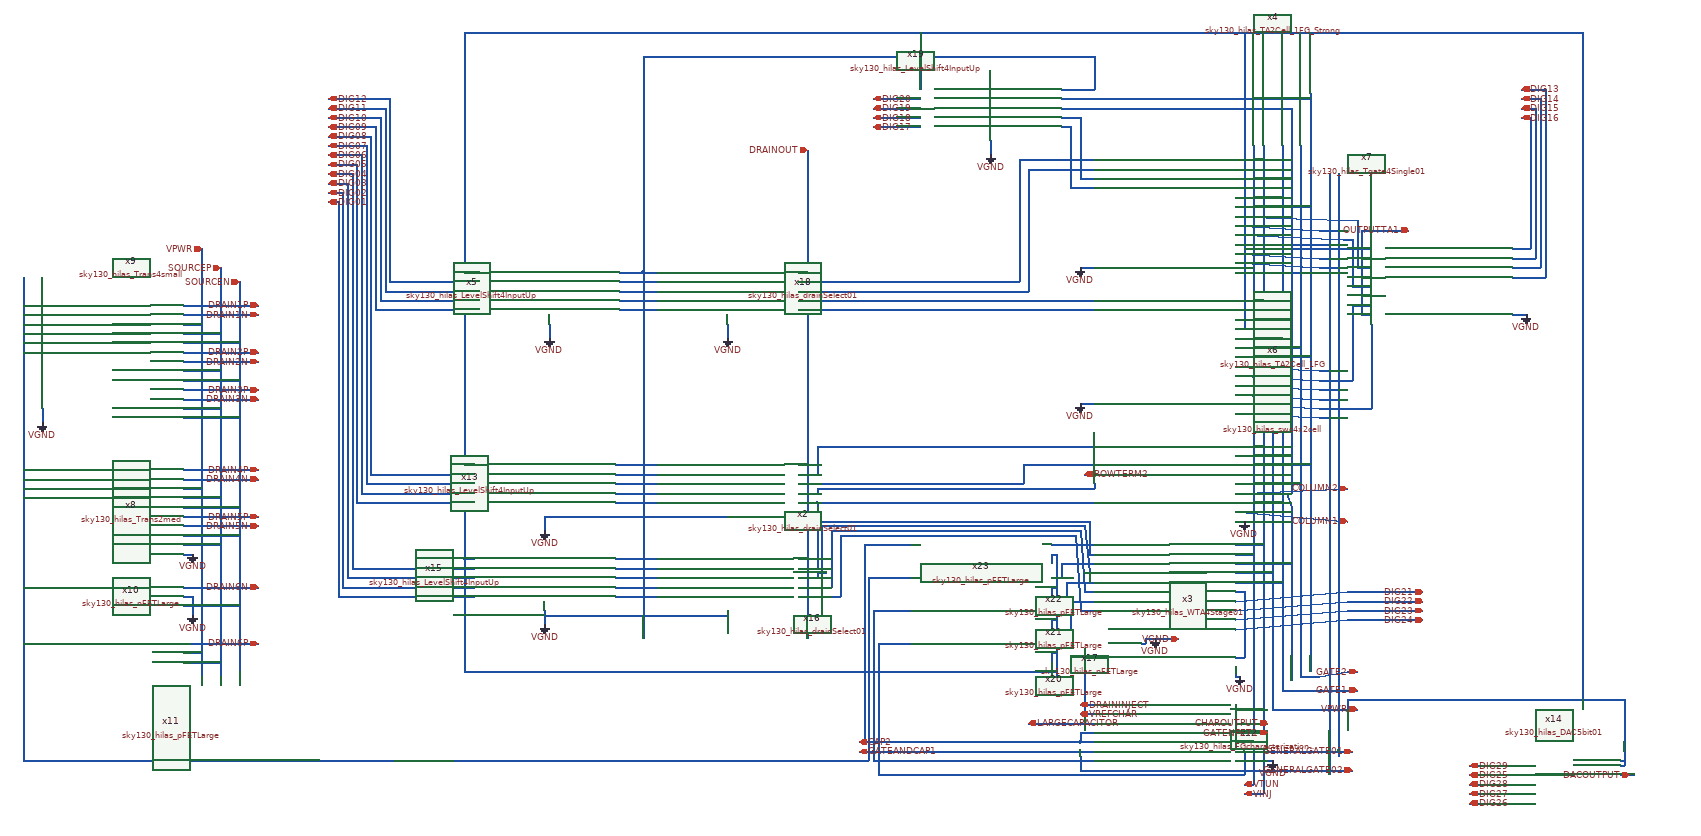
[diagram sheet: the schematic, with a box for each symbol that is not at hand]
v {xschem version=2.9.9 file_version=1.2 }
G {}
K {}
V {}
S {}
E {}
N 800 -10 800 440 { lab=VTUN}
N -500 -10 -500 430 { lab=#net1}
N 820 -10 820 440 { lab=VINJ}
N -500 60 -470 60 { lab=#net1}
N -500 260 -470 260 { lab=#net1}
N 760 20 820 20 { lab=VINJ}
N 760 230 820 230 { lab=VINJ}
N 760 80 800 80 { lab=VTUN}
N 760 250 800 250 { lab=VTUN}
N 840 -10 840 440 { lab=VPWR}
N 760 290 840 290 { lab=VPWR}
N 760 330 780 330 { lab=#net2}
N 780 330 780 460 { lab=#net2}
N -150 -10 -150 430 { lab=DRAINOUT}
N -170 60 -150 60 { lab=DRAINOUT}
N -170 260 -150 260 { lab=DRAINOUT}
N 300 20 460 20 { lab=#net3}
N -130 30 -130 80 { lab=#net3}
N -170 80 -130 80 { lab=#net3}
N 300 140 460 140 { lab=#net4}
N -130 140 -130 150 { lab=#net4}
N -170 140 -130 140 { lab=#net4}
N 300 110 460 110 { lab=#net5}
N -130 110 -130 120 { lab=#net5}
N -170 120 -130 120 { lab=#net5}
N 310 60 460 60 { lab=#net6}
N 310 70 310 100 { lab=#net6}
N -170 100 -120 100 { lab=#net6}
N -170 280 -130 280 { lab=#net7}
N -130 250 -130 280 { lab=#net7}
N -170 340 -130 340 { lab=#net8}
N -170 320 -130 320 { lab=#net9}
N -130 290 -110 290 { lab=#net10}
N -130 290 -130 300 { lab=#net10}
N -170 300 -130 300 { lab=#net10}
N 860 -10 860 500 { lab=GATE1}
N 900 -10 900 500 { lab=GATE2}
N 760 310 860 310 { lab=GATE1}
N 760 140 860 140 { lab=GATE1}
N 920 -10 920 500 { lab=#net11}
N 880 -10 880 120 { lab=#net12}
N 880 150 880 500 { lab=#net12}
N 760 40 880 40 { lab=#net12}
N 760 270 880 270 { lab=#net12}
N 760 60 920 60 { lab=#net11}
N 870 120 880 150 { lab=#net12}
N 870 120 880 120 { lab=#net12}
N 820 440 820 550 { lab=VINJ}
N 820 550 820 720 { lab=VINJ}
N 800 440 800 660 { lab=VTUN}
N 760 650 800 650 { lab=VTUN}
N 760 580 820 580 { lab=VINJ}
N 820 720 820 740 { lab=VINJ}
N 800 660 800 720 { lab=VTUN}
N 820 740 820 760 { lab=VINJ}
N 780 760 820 760 { lab=VINJ}
N 770 630 790 630 { lab=GATENFET1}
N 430 690 460 690 { lab=GENERALGATE02}
N 430 670 460 670 { lab=GATEANDCAP1}
N 430 650 460 650 { lab=CAP2}
N 430 610 460 610 { lab=LARGECAPACITOR}
N 430 590 460 590 { lab=VREFCHAR}
N 430 570 460 570 { lab=DRAININJECT}
N 800 -520 800 -70 { lab=VTUN}
N 820 -520 820 -70 { lab=VINJ}
N 860 -520 860 -10 { lab=GATE1}
N 900 -520 900 -10 { lab=GATE2}
N 920 -520 920 -10 { lab=#net11}
N 880 -520 880 -10 { lab=#net12}
N 800 -70 800 -10 { lab=VTUN}
N 820 -70 820 -10 { lab=VINJ}
N -150 -450 -150 -10 { lab=DRAINOUT}
N -150 -610 -150 -450 { lab=DRAINOUT}
N -170 -350 -150 -350 { lab=DRAINOUT}
N 300 -270 460 -270 { lab=#net13}
N 300 -290 460 -290 { lab=#net14}
N -170 -290 -130 -290 { lab=#net14}
N -170 -270 -130 -270 { lab=#net13}
N -500 -350 -500 -10 { lab=#net1}
N -500 -350 -470 -350 { lab=#net1}
N 430 -610 430 -550 { lab=#net15}
N 410 -610 410 -530 { lab=#net16}
N 430 -550 460 -550 { lab=#net15}
N 410 -530 460 -530 { lab=#net16}
N -170 -330 -130 -330 { lab=#net17}
N 300 -590 300 -330 { lab=#net17}
N 300 -590 460 -590 { lab=#net17}
N -170 -310 -110 -310 { lab=#net18}
N 320 -570 320 -310 { lab=#net18}
N 320 -570 460 -570 { lab=#net18}
N 800 -620 800 -520 { lab=VTUN}
N 820 -620 820 -520 { lab=VINJ}
N 860 -620 860 -520 { lab=GATE1}
N 880 -620 880 -520 { lab=#net12}
N 900 -620 900 -520 { lab=GATE2}
N 920 -620 920 -520 { lab=#net11}
N 760 -590 820 -590 { lab=VINJ}
N 760 -570 800 -570 { lab=VTUN}
N 760 -290 820 -290 { lab=VINJ}
N 760 -270 800 -270 { lab=VTUN}
N 760 -250 880 -250 { lab=#net12}
N 760 -550 880 -550 { lab=#net12}
N 760 -490 920 -490 { lab=#net11}
N 760 -170 920 -170 { lab=#net11}
N 760 -510 860 -510 { lab=GATE1}
N 760 -210 860 -210 { lab=GATE1}
N 760 -190 900 -190 { lab=GATE2}
N 760 -350 900 -350 { lab=GATE2}
N 780 -620 780 -230 { lab=VPWR}
N 760 -230 780 -230 { lab=VPWR}
N 760 -530 780 -530 { lab=VPWR}
N 1030 -440 1030 -260 { lab=OUTPUTTA1}
N 1030 -260 1050 -260 { lab=OUTPUTTA1}
N 1030 -300 1050 -300 { lab=OUTPUTTA1}
N 1030 -340 1050 -340 { lab=OUTPUTTA1}
N 1030 -380 1050 -380 { lab=OUTPUTTA1}
N 780 -400 1050 -400 { lab=VPWR}
N 1050 -240 1050 -60 { lab=#net19}
N 760 -70 780 -70 { lab=#net19}
N 780 -70 940 -60 { lab=#net19}
N 940 -60 1050 -60 { lab=#net19}
N 760 -130 940 -120 { lab=#net20}
N 940 -120 1010 -120 { lab=#net20}
N 1010 -280 1010 -120 { lab=#net20}
N 1010 -280 1050 -280 { lab=#net20}
N 1020 -460 1020 -360 { lab=#net21}
N 760 -470 1020 -460 { lab=#net21}
N 760 -430 990 -420 { lab=#net22}
N 1020 -360 1050 -360 { lab=#net21}
N 1010 -320 1050 -320 { lab=#net22}
N 1010 -420 1010 -320 { lab=#net22}
N 990 -420 1010 -420 { lab=#net22}
N 1030 -440 1110 -440 { lab=OUTPUTTA1}
N 1110 -440 1130 -440 { lab=OUTPUTTA1}
N 760 670 1010 670 { lab=GENERALGATE01}
N 760 710 1010 710 { lab=GENERALGATE02}
N 960 -560 960 520 { lab=#net23}
N 980 -560 980 520 { lab=GENERALGATE01}
N 980 520 980 680 { lab=GENERALGATE01}
N 960 520 960 700 { lab=#net23}
N 840 440 840 580 { lab=VPWR}
N 840 580 1020 580 { lab=VPWR}
N 760 -50 940 -40 { lab=#net23}
N 940 -40 960 -40 { lab=#net23}
N 760 -90 940 -80 { lab=GENERALGATE01}
N 940 -80 980 -80 { lab=GENERALGATE01}
N 760 -110 940 -100 { lab=GENERALGATE01}
N 940 -100 980 -100 { lab=GENERALGATE01}
N 760 -150 940 -140 { lab=#net23}
N 940 -140 960 -140 { lab=#net23}
N 760 -450 940 -440 { lab=GENERALGATE01}
N 940 -440 980 -440 { lab=GENERALGATE01}
N 760 -370 940 -360 { lab=GENERALGATE01}
N 940 -360 980 -360 { lab=GENERALGATE01}
N 760 -390 940 -380 { lab=#net23}
N 940 -380 960 -380 { lab=#net23}
N 760 -410 960 -410 { lab=#net23}
N 860 540 1020 540 { lab=GATE1}
N 860 500 860 540 { lab=GATE1}
N 880 500 880 520 { lab=#net12}
N 900 500 900 510 { lab=GATE2}
N 900 510 940 510 { lab=GATE2}
N 1000 500 1020 500 { lab=GATE2}
N 940 510 1000 500 { lab=GATE2}
N -1820 -340 -1820 510 { lab=GATEANDCAP1}
N -1820 -280 -1780 -280 { lab=GATEANDCAP1}
N -1820 -260 -1780 -260 { lab=GATEANDCAP1}
N -1820 -240 -1780 -240 { lab=GATEANDCAP1}
N -1820 -220 -1780 -220 { lab=GATEANDCAP1}
N -1820 -200 -1780 -200 { lab=GATEANDCAP1}
N -1820 -180 -1780 -180 { lab=GATEANDCAP1}
N -1820 70 -1780 70 { lab=GATEANDCAP1}
N -1820 90 -1780 90 { lab=GATEANDCAP1}
N -1820 110 -1780 110 { lab=GATEANDCAP1}
N -1820 130 -1780 130 { lab=GATEANDCAP1}
N -1820 320 -1780 320 { lab=GATEANDCAP1}
N -1820 440 -1780 440 { lab=GATEANDCAP1}
N -1440 -310 -1440 510 { lab=VPWR}
N -1400 -310 -1400 510 { lab=SOURCEP}
N -1360 -310 -1360 500 { lab=SOURCEN}
N -1480 -240 -1440 -240 { lab=VPWR}
N -1480 110 -1440 110 { lab=VPWR}
N -1480 460 -1440 460 { lab=VPWR}
N -1480 -220 -1400 -220 { lab=SOURCEP}
N -1480 -200 -1360 -200 { lab=SOURCEN}
N -1480 -140 -1400 -140 { lab=SOURCEP}
N -1480 -120 -1360 -120 { lab=SOURCEN}
N -1480 -60 -1400 -60 { lab=SOURCEP}
N -1480 -40 -1360 -40 { lab=SOURCEN}
N -1480 130 -1400 130 { lab=SOURCEP}
N -1480 150 -1360 150 { lab=SOURCEN}
N -1480 230 -1400 230 { lab=SOURCEP}
N -1480 210 -1360 210 { lab=SOURCEN}
N -1480 360 -1360 360 { lab=SOURCEN}
N -1480 480 -1400 480 { lab=SOURCEP}
N 320 670 430 670 { lab=GATEANDCAP1}
N -470 690 -80 690 { lab=GATEANDCAP1}
N -540 690 -470 690 { lab=GATEANDCAP1}
N -1820 690 -1190 690 { lab=GATEANDCAP1}
N -1820 510 -1820 690 { lab=GATEANDCAP1}
N -1480 -280 -1320 -280 { lab=DRAIN1P}
N -1480 -260 -1320 -260 { lab=DRAIN1N}
N -1480 -180 -1320 -180 { lab=DRAIN2P}
N -1480 -160 -1320 -160 { lab=DRAIN2N}
N -1480 -100 -1320 -100 { lab=DRAIN3P}
N -1480 -80 -1320 -80 { lab=DRAIN3N}
N -1480 70 -1320 70 { lab=DRAIN4P}
N -1480 90 -1320 90 { lab=DRAIN4N}
N -1480 170 -1320 170 { lab=DRAIN5P}
N -1480 190 -1320 190 { lab=DRAIN5N}
N -1480 320 -1320 320 { lab=DRAIN6N}
N -1480 440 -1320 440 { lab=DRAIN6P}
N -1360 -330 -1360 -310 { lab=SOURCEN}
N -1400 -360 -1400 -310 { lab=SOURCEP}
N -1440 -400 -1440 -310 { lab=VPWR}
N 410 -640 410 -610 { lab=#net16}
N 440 270 460 270 { lab=#net24}
N 440 230 460 230 { lab=#net25}
N 440 350 460 350 { lab=#net26}
N 1000 560 1000 580 { lab=VPWR}
N 1000 560 1590 560 { lab=VPWR}
N 1590 560 1590 690 { lab=VPWR}
N 1580 690 1590 690 { lab=VPWR}
N 960 700 960 720 { lab=#net23}
N 1270 720 1280 720 { lab=DIG25}
N 1580 700 1590 700 { lab=VPWR}
N 1590 670 1590 700 { lab=VPWR}
N 370 650 430 650 { lab=CAP2}
N 320 650 370 650 { lab=CAP2}
N 390 610 430 610 { lab=LARGECAPACITOR}
N 320 610 390 610 { lab=LARGECAPACITOR}
N 1580 720 1610 720 { lab=DACOUTPUT}
N 760 350 1000 330 { lab=DIG21}
N 760 370 1000 350 { lab=DIG22}
N 760 390 1000 370 { lab=DIG23}
N 760 410 1000 390 { lab=DIG24}
N 440 80 460 80 { lab=ROWTERM2}
N -1030 690 -540 690 { lab=GATEANDCAP1}
N -1200 690 -1000 690 { lab=GATEANDCAP1}
N -550 -350 -500 -350 { lab=#net1}
N -550 -330 -470 -330 { lab=#net27}
N -550 -310 -470 -310 { lab=#net28}
N -550 -290 -470 -290 { lab=#net29}
N -550 -270 -470 -270 { lab=#net30}
N -560 60 -500 60 { lab=#net1}
N -560 80 -470 80 { lab=#net31}
N -560 100 -470 100 { lab=#net32}
N -560 120 -470 120 { lab=#net33}
N -560 140 -470 140 { lab=#net34}
N -560 260 -500 260 { lab=#net1}
N -560 280 -470 280 { lab=#net35}
N -560 300 -470 300 { lab=#net36}
N -560 320 -470 320 { lab=#net37}
N -560 340 -470 340 { lab=#net38}
N -880 -420 -880 260 { lab=VPWR}
N 1350 -400 1390 -400 { lab=DIG16}
N 1390 -680 1390 -400 { lab=DIG16}
N 1370 -680 1390 -680 { lab=DIG16}
N 1350 -380 1400 -380 { lab=DIG15}
N 1400 -700 1400 -380 { lab=DIG15}
N 1370 -700 1400 -700 { lab=DIG15}
N 1350 -360 1410 -360 { lab=DIG14}
N 1410 -720 1410 -360 { lab=DIG14}
N 1370 -720 1410 -720 { lab=DIG14}
N 1350 -340 1420 -340 { lab=DIG13}
N 1420 -740 1420 -340 { lab=DIG13}
N 1370 -740 1420 -740 { lab=DIG13}
N -1170 -500 -1150 -500 { lab=DIG01}
N -1150 -500 -1150 -420 { lab=DIG01}
N -1170 -520 -1140 -520 { lab=DIG02}
N -1140 -520 -1140 -420 { lab=DIG02}
N -1170 -540 -1130 -540 { lab=DIG03}
N -1130 -540 -1130 -420 { lab=DIG03}
N -1170 -560 -1120 -560 { lab=DIG04}
N -1120 -560 -1120 -420 { lab=DIG04}
N -1170 -580 -1110 -580 { lab=DIG05}
N -1110 -580 -1110 -420 { lab=DIG05}
N -1170 -600 -1110 -600 { lab=DIG06}
N -1110 -600 -1100 -600 { lab=DIG06}
N -1100 -600 -1100 -420 { lab=DIG06}
N -1170 -620 -1090 -620 { lab=DIG07}
N -1090 -620 -1090 -420 { lab=DIG07}
N -1170 -640 -1080 -640 { lab=DIG08}
N -1080 -640 -1080 -420 { lab=DIG08}
N -1170 -660 -1070 -660 { lab=DIG09}
N -1070 -660 -1070 -420 { lab=DIG09}
N -1170 -680 -1060 -680 { lab=DIG10}
N -1060 -680 -1060 -420 { lab=DIG10}
N -1170 -700 -1050 -700 { lab=DIG11}
N -1050 -700 -1050 -420 { lab=DIG11}
N -1170 -720 -1040 -720 { lab=DIG12}
N -1040 -720 -1040 -420 { lab=DIG12}
N -1040 -330 -850 -330 { lab=DIG12}
N -1040 -420 -1040 -330 { lab=DIG12}
N -1050 -310 -850 -310 { lab=DIG11}
N -1050 -420 -1050 -310 { lab=DIG11}
N -1060 -290 -850 -290 { lab=DIG10}
N -1060 -420 -1060 -290 { lab=DIG10}
N -1070 -270 -850 -270 { lab=DIG09}
N -1070 -420 -1070 -270 { lab=DIG09}
N -1080 -420 -1080 20 { lab=DIG08}
N -1090 -420 -1090 20 { lab=DIG07}
N -1100 -420 -1100 20 { lab=DIG06}
N -1110 -420 -1110 20 { lab=DIG05}
N -1120 -420 -1120 20 { lab=DIG04}
N -1130 -420 -1130 20 { lab=DIG03}
N -1140 -420 -1140 20 { lab=DIG02}
N -1150 -420 -1150 20 { lab=DIG01}
N -1070 80 -860 80 { lab=DIG08}
N -1070 100 -860 100 { lab=DIG07}
N -1070 120 -860 120 { lab=DIG06}
N -1070 140 -860 140 { lab=DIG05}
N -880 60 -860 60 { lab=VPWR}
N -880 260 -860 260 { lab=VPWR}
N -1060 280 -860 280 { lab=DIG04}
N -1060 300 -860 300 { lab=DIG03}
N -1060 320 -860 320 { lab=DIG02}
N -1060 340 -860 340 { lab=DIG01}
N -1150 20 -1150 270 { lab=DIG01}
N -1140 20 -1140 260 { lab=DIG02}
N -1130 20 -1130 270 { lab=DIG03}
N -1120 20 -1120 270 { lab=DIG04}
N -1080 20 -1080 80 { lab=DIG08}
N -1080 80 -1070 80 { lab=DIG08}
N -1090 20 -1090 100 { lab=DIG07}
N -1090 100 -1070 100 { lab=DIG07}
N -1100 20 -1100 120 { lab=DIG06}
N -1100 120 -1070 120 { lab=DIG06}
N -1110 20 -1110 140 { lab=DIG05}
N -1110 140 -1070 140 { lab=DIG05}
N -1120 280 -1060 280 { lab=DIG04}
N -1120 270 -1120 280 { lab=DIG04}
N -1130 300 -1060 300 { lab=DIG03}
N -1140 320 -1060 320 { lab=DIG02}
N -1150 340 -1060 340 { lab=DIG01}
N -1130 270 -1130 300 { lab=DIG03}
N -1140 260 -1140 320 { lab=DIG02}
N -1150 270 -1150 340 { lab=DIG01}
N 1500 100 1500 560 { lab=VPWR}
N 1500 -860 1500 90 { lab=VPWR}
N -880 -860 1070 -860 { lab=VPWR}
N -880 -860 -880 -420 { lab=VPWR}
N -880 -350 -850 -350 { lab=VPWR}
N 90 -860 90 -740 { lab=VPWR}
N 410 -660 410 -640 { lab=#net16}
N 390 -660 410 -660 { lab=#net16}
N 430 -680 430 -610 { lab=#net15}
N 390 -680 430 -680 { lab=#net15}
N -500 -610 -500 -350 { lab=#net1}
N -140 -810 460 -810 { lab=#net1}
N 460 -810 460 -740 { lab=#net1}
N 390 -740 460 -740 { lab=#net1}
N 390 -720 850 -720 { lab=#net11}
N 390 -700 790 -700 { lab=#net12}
N 920 -730 920 -620 { lab=#net11}
N 850 -720 920 -720 { lab=#net11}
N 880 -700 880 -620 { lab=#net12}
N 790 -700 880 -700 { lab=#net12}
N 1000 330 1160 330 { lab=DIG21}
N 1000 350 1160 350 { lab=DIG22}
N 1000 370 1160 370 { lab=DIG23}
N 1000 390 1160 390 { lab=DIG24}
N 1260 760 1280 760 { lab=DIG27}
N 1260 780 1280 780 { lab=DIG26}
N 1260 720 1280 720 { lab=DIG25}
N 1260 740 1280 740 { lab=DIG28}
N 1260 700 1280 700 { lab=DIG29}
N -10 -660 80 -660 { lab=DIG17}
N -10 -680 80 -680 { lab=DIG18}
N -10 -700 80 -700 { lab=DIG19}
N -10 -720 80 -720 { lab=DIG20}
N 80 -720 90 -720 { lab=DIG20}
N 70 -700 90 -700 { lab=DIG19}
N 80 -680 90 -680 { lab=DIG18}
N 80 -660 90 -660 { lab=DIG17}
N -500 -810 -140 -810 { lab=#net1}
N -500 -810 -500 -610 { lab=#net1}
N -130 -330 300 -330 { lab=#net17}
N -110 -310 320 -310 { lab=#net18}
N -130 -290 300 -290 { lab=#net14}
N -130 -270 300 -270 { lab=#net13}
N -130 20 300 20 { lab=#net3}
N -120 100 310 100 { lab=#net6}
N -130 110 300 110 { lab=#net5}
N -130 140 300 140 { lab=#net4}
N 1080 -860 1500 -860 { lab=VPWR}
N 1070 -860 1080 -860 { lab=VPWR}
N 370 460 370 480 { lab=VPWR}
N 370 390 370 410 { lab=VPWR}
N 370 320 370 340 { lab=VPWR}
N 370 250 370 270 { lab=VPWR}
N 370 230 440 230 { lab=#net25}
N 450 250 460 250 { lab=#net7}
N 450 180 450 250 { lab=#net7}
N -130 180 450 180 { lab=#net7}
N -130 180 -130 230 { lab=#net7}
N -130 230 -130 250 { lab=#net7}
N 390 270 440 270 { lab=#net24}
N 370 300 390 300 { lab=#net24}
N 440 290 460 290 { lab=#net10}
N 440 190 450 290 { lab=#net10}
N -120 190 440 190 { lab=#net10}
N -120 190 -120 290 { lab=#net10}
N 440 330 460 330 { lab=#net9}
N 430 200 440 330 { lab=#net9}
N -100 200 430 200 { lab=#net9}
N -100 200 -100 320 { lab=#net9}
N -120 320 -100 320 { lab=#net9}
N -130 320 -120 320 { lab=#net9}
N 420 310 460 310 { lab=#net39}
N 380 250 380 510 { lab=VPWR}
N 370 250 380 250 { lab=VPWR}
N 370 320 380 320 { lab=VPWR}
N 370 390 380 390 { lab=VPWR}
N 370 460 380 460 { lab=VPWR}
N 430 370 460 370 { lab=#net8}
N 420 210 430 370 { lab=#net8}
N -80 210 420 210 { lab=#net8}
N -80 210 -80 340 { lab=#net8}
N -130 340 -80 340 { lab=#net8}
N 390 270 390 300 { lab=#net24}
N 370 370 400 370 { lab=#net39}
N 400 310 400 370 { lab=#net39}
N 400 310 420 310 { lab=#net39}
N 410 350 440 350 { lab=#net26}
N 410 350 410 420 { lab=#net26}
N 370 440 410 440 { lab=#net26}
N 410 420 410 440 { lab=#net26}
N -40 670 -20 670 { lab=GATEANDCAP1}
N -20 660 -20 690 { lab=GATEANDCAP1}
N -80 690 -20 690 { lab=GATEANDCAP1}
N -40 650 -30 650 { lab=CAP2}
N -30 230 -30 640 { lab=CAP2}
N -30 230 70 230 { lab=CAP2}
N -20 300 -20 660 { lab=GATEANDCAP1}
N -20 300 70 300 { lab=GATEANDCAP1}
N -30 650 320 650 { lab=CAP2}
N -20 670 320 670 { lab=GATEANDCAP1}
N -10 370 70 370 { lab=GENERALGATE02}
N -10 370 -10 680 { lab=GENERALGATE02}
N -10 690 370 690 { lab=GENERALGATE02}
N -0 440 70 440 { lab=GENERALGATE01}
N -0 440 0 720 { lab=GENERALGATE01}
N 0 720 370 720 { lab=GENERALGATE01}
N 780 -860 780 -620 { lab=VPWR}
N -880 260 -880 490 { lab=VPWR}
N -880 490 -880 500 { lab=VPWR}
N -880 500 380 500 { lab=VPWR}
N 370 690 430 690 { lab=GENERALGATE02}
N 430 680 430 700 { lab=GENERALGATE02}
N 430 710 740 710 { lab=GENERALGATE02}
N 370 720 710 720 { lab=GENERALGATE01}
N 800 720 800 740 { lab=VTUN}
N 780 740 800 740 { lab=VTUN}
N 740 710 760 710 { lab=GENERALGATE02}
N 710 720 780 720 { lab=GENERALGATE01}
N 780 680 780 720 { lab=GENERALGATE01}
N 1500 90 1500 100 { lab=VPWR}
N -1780 -60 -1780 -30 { lab=VGND}
N -710 370 -710 400 { lab=VGND}
N -710 170 -710 200 { lab=VGND}
N -700 -240 -700 -210 { lab=VGND}
N 240 -630 240 -600 { lab=VGND}
N 430 -360 460 -360 { lab=VGND}
N 430 -70 460 -70 { lab=VGND}
N 760 570 760 590 { lab=VINJ}
N 440 460 440 590 { lab=VREFCHAR}
N 760 610 830 610 { lab=CHAROUTPUT}
N 760 630 830 630 { lab=GATENFET1}
N 780 670 780 680 { lab=GENERALGATE01}
N 980 670 980 680 { lab=GENERALGATE01}
N 430 700 430 710 { lab=GENERALGATE02}
N 760 690 840 690 { lab=VGND}
N -10 680 -10 690 { lab=GENERALGATE02}
N -30 640 -30 650 { lab=CAP2}
N 430 630 460 630 { lab=CAP2}
N 430 630 430 650 { lab=CAP2}
N 1350 -260 1380 -260 { lab=VGND}
N -320 -240 -320 -210 { lab=VGND}
N -320 370 -320 380 { lab=VGND}
N -710 380 -320 380 { lab=VGND}
N -710 170 -320 170 { lab=VGND}
N 760 470 780 470 { lab=#net2}
N 440 450 440 460 { lab=VREFCHAR}
N 570 430 590 430 { lab=VGND}
N 570 430 570 440 { lab=VGND}
N 560 440 570 440 { lab=VGND}
N 440 470 460 470 { lab=VREFCHAR}
N 760 510 770 510 { lab=VGND}
N 760 160 1000 180 { lab=COLUMN1}
N 780 460 780 470 { lab=#net2}
N 760 120 1000 110 { lab=COLUMN2}
N 760 100 900 100 { lab=GATE2}
N 590 430 640 430 { lab=VGND}
N -130 20 -130 30 { lab=#net3}
N 310 60 310 70 { lab=#net6}
N 460 100 460 110 { lab=#net5}
N 760 180 780 180 { lab=VGND}
N 760 490 760 510 { lab=VGND}
N -1480 250 -1460 250 { lab=VGND}
N -1460 340 -1460 380 { lab=VGND}
N -1480 340 -1460 340 { lab=VGND}
C {sky130_hilas_swc4x2cell.sym} 610 100 0 0 {name=x1}
C {sky130_hilas_drainSelect01.sym} -320 100 0 0 {name=x2}
C {sky130_hilas_WTA4Stage01.sym} 610 320 0 0 {name=x3}
C {sky130_hilas_TA2Cell_1FG_Strong.sym} 610 -470 0 0 {name=x4}
C {sky130_hilas_TA2Cell_1FG.sym} 610 -170 0 0 {name=x6}
C {sky130_hilas_Tgate4Single01.sym} 1200 -320 0 1 {name=x7}
C {sky130_hilas_Trans2med.sym} -1630 160 0 0 {name=x8}
C {sky130_hilas_Trans4small.sym} -1630 -160 0 0 {name=x9}
C {sky130_hilas_nFETLarge.sym} -1630 340 0 0 {name=x10}
C {sky130_hilas_pFETLarge.sym} -1630 460 0 0 {name=x11}
C {sky130_hilas_FGcharacterization01.sym} 610 630 0 0 {name=x12}
C {sky130_hilas_DAC5bit01.sym} 1430 740 0 0 {name=x14}
C {sky130_hilas_drainSelect01.sym} -320 300 0 0 {name=x16}
C {sky130_hilas_nFETLarge.sym} 610 490 0 0 {name=x17}
C {sky130_hilas_drainSelect01.sym} -320 -310 0 0 {name=x18}
C {devices/iopin.sym} 780 740 0 1 {name=Vtun lab=VTUN}
C {devices/iopin.sym} 780 760 0 1 {name=Vinj lab=VINJ}
C {devices/iopin.sym} 830 630 0 0 {name=GateNFET1 lab=GATENFET1}
C {devices/iopin.sym} 830 610 0 0 {name=CharOutput lab=CHAROUTPUT}
C {devices/iopin.sym} 430 570 0 1 {name=DrainInject lab=DRAININJECT}
C {devices/iopin.sym} 430 590 0 1 {name=VrefChar lab=VREFCHAR}
C {devices/iopin.sym} 320 610 0 1 {name=LargeCapacitor lab=LARGECAPACITOR}
C {devices/iopin.sym} -40 650 0 1 {name=Cap2 lab=CAP2}
C {devices/iopin.sym} -40 670 0 1 {name=GateAndCap1 lab=GATEANDCAP1}
C {devices/iopin.sym} 1010 670 0 0 {name=GeneralGate01 lab=GENERALGATE01}
C {devices/iopin.sym} 1010 710 0 0 {name=GeneralGate02 lab=GENERALGATE02}
C {devices/iopin.sym} 1130 -440 0 0 {name=OutputTA1 lab=OUTPUTTA1}
C {devices/iopin.sym} 1020 580 0 0 {name=VPWR lab=VPWR}
C {devices/iopin.sym} 1020 540 0 0 {name=Gate1 lab=GATE1}
C {devices/iopin.sym} 1020 500 0 0 {name=Gate2 lab=GATE2}
C {devices/iopin.sym} -1320 -280 0 0 {name=Drain1p lab=DRAIN1P}
C {devices/iopin.sym} -1320 -260 0 0 {name=Drain1n lab=DRAIN1N}
C {devices/iopin.sym} -1320 -180 0 0 {name=Drain2p lab=DRAIN2P}
C {devices/iopin.sym} -1320 -160 0 0 {name=Drain2n lab=DRAIN2N}
C {devices/iopin.sym} -1320 -100 0 0 {name=Drain3p lab=DRAIN3P}
C {devices/iopin.sym} -1320 -80 0 0 {name=Drain3n lab=DRAIN3N}
C {devices/iopin.sym} -1320 70 0 0 {name=Drain4p lab=DRAIN4P}
C {devices/iopin.sym} -1320 90 0 0 {name=Drain4n lab=DRAIN4N}
C {devices/iopin.sym} -1320 170 0 0 {name=Drain5p lab=DRAIN5P}
C {devices/iopin.sym} -1320 190 0 0 {name=Drain5n lab=DRAIN5N}
C {devices/iopin.sym} -1320 440 0 0 {name=Drain6p lab=DRAIN6P}
C {devices/iopin.sym} -1320 320 0 0 {name=Drain16n lab=DRAIN6N}
C {devices/iopin.sym} -1360 -330 0 0 {name=SourceN lab=SOURCEN}
C {devices/iopin.sym} -1400 -360 0 0 {name=SourceP lab=SOURCEP}
C {devices/iopin.sym} -1440 -400 0 0 {name=Well lab=VPWR}
C {devices/iopin.sym} -150 -610 0 0 {name=DrainOut lab=DRAINOUT}
C {devices/iopin.sym} 440 80 0 1 {name=RowTerm2 lab=ROWTERM2}
C {devices/iopin.sym} 1000 180 0 0 {name=Column1 lab=COLUMN1}
C {devices/iopin.sym} 1000 110 0 0 {name=Column2 lab=COLUMN2}
C {devices/iopin.sym} 1600 720 0 0 {name=DacOutput lab=DACOUTPUT}
C {sky130_hilas_LevelShift4InputUp.sym} -700 -310 0 0 {name=x5}
C {sky130_hilas_LevelShift4InputUp.sym} -710 100 0 0 {name=x13}
C {sky130_hilas_LevelShift4InputUp.sym} -710 300 0 0 {name=x15}
C {devices/iopin.sym} -1170 -500 0 1 {name=Dig01 lab=DIG01}
C {devices/iopin.sym} -1170 -520 0 1 {name=Dig02 lab=DIG02}
C {devices/iopin.sym} -1170 -540 0 1 {name=Dig03 lab=DIG03}
C {devices/iopin.sym} -1170 -560 0 1 {name=Dig04 lab=DIG04}
C {devices/iopin.sym} -1170 -580 0 1 {name=Dig05 lab=DIG05}
C {devices/iopin.sym} -1170 -600 0 1 {name=Dig06 lab=DIG06}
C {devices/iopin.sym} -1170 -620 0 1 {name=Dig07 lab=DIG07}
C {devices/iopin.sym} -1170 -640 0 1 {name=Dig08 lab=DIG08}
C {devices/iopin.sym} -1170 -660 0 1 {name=Dig09 lab=DIG09}
C {devices/iopin.sym} -1170 -680 0 1 {name=Dig10 lab=DIG10}
C {devices/iopin.sym} -1170 -700 0 1 {name=Dig11 lab=DIG11}
C {devices/iopin.sym} -1170 -720 0 1 {name=Dig12 lab=DIG12}
C {devices/iopin.sym} 1370 -680 0 1 {name=Dig16 lab=DIG16}
C {devices/iopin.sym} 1370 -700 0 1 {name=Dig15 lab=DIG15}
C {devices/iopin.sym} 1370 -720 0 1 {name=Dig14 lab=DIG14}
C {devices/iopin.sym} 1370 -740 0 1 {name=Dig13 lab=DIG13}
C {sky130_hilas_LevelShift4InputUp.sym} 240 -700 0 0 {name=x19}
C {devices/iopin.sym} 1160 330 0 0 {name=Dig21 lab=DIG21}
C {devices/iopin.sym} 1160 350 0 0 {name=Dig22 lab=DIG22}
C {devices/iopin.sym} 1160 370 0 0 {name=Dig23 lab=DIG23}
C {devices/iopin.sym} 1160 390 0 0 {name=Dig24 lab=DIG24}
C {sky130_hilas_pFETLarge.sym} 220 460 0 0 {name=x20}
C {devices/iopin.sym} 1260 720 0 1 {name=Dig25 lab=DIG25}
C {devices/iopin.sym} 1260 780 0 1 {name=Dig26 lab=DIG26}
C {devices/iopin.sym} 1260 760 0 1 {name=Dig27 lab=DIG27}
C {devices/iopin.sym} 1260 740 0 1 {name=Dig28 lab=DIG28}
C {devices/iopin.sym} 1260 700 0 1 {name=Dig29 lab=DIG29}
C {devices/iopin.sym} -10 -660 0 1 {name=Dig17 lab=DIG17}
C {devices/iopin.sym} -10 -680 0 1 {name=Dig18 lab=DIG18}
C {devices/iopin.sym} -10 -700 0 1 {name=Dig19 lab=DIG19}
C {devices/iopin.sym} -10 -720 0 1 {name=Dig20 lab=DIG20}
C {sky130_hilas_pFETLarge.sym} 220 390 0 0 {name=x21}
C {sky130_hilas_pFETLarge.sym} 220 320 0 0 {name=x22}
C {sky130_hilas_pFETLarge.sym} 220 250 0 0 {name=x23}
C {devices/gnd.sym} -1780 -30 0 0 {name=l2 lab=VGND}
C {devices/gnd.sym} -700 -210 0 0 {name=l3 lab=VGND}
C {devices/gnd.sym} -710 200 0 0 {name=l4 lab=VGND}
C {devices/gnd.sym} -710 400 0 0 {name=l5 lab=VGND}
C {devices/gnd.sym} 240 -600 0 0 {name=l6 lab=VGND}
C {devices/gnd.sym} 430 -360 0 0 {name=l7 lab=VGND}
C {devices/gnd.sym} 430 -70 0 0 {name=l8 lab=VGND}
C {devices/gnd.sym} 590 430 0 0 {name=l9 lab=VGND}
C {devices/gnd.sym} 840 690 0 0 {name=l11 lab=VGND}
C {devices/gnd.sym} 1380 -260 0 0 {name=l12 lab=VGND}
C {devices/gnd.sym} -320 -210 0 0 {name=l13 lab=VGND}
C {devices/gnd.sym} 770 510 0 0 {name=l1 lab=VGND}
C {devices/iopin.sym} 640 430 0 0 {name=VGND lab=VGND}
C {devices/gnd.sym} 780 180 0 0 {name=l10 lab=VGND}
C {devices/gnd.sym} -1460 250 0 0 {name=l14 lab=VGND}
C {devices/gnd.sym} -1460 380 0 0 {name=l15 lab=VGND}
